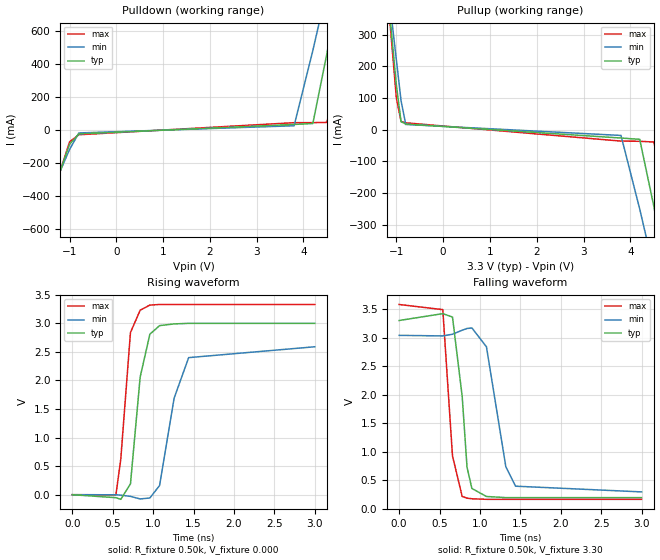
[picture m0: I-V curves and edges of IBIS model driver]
| IBIS file buffer.ibs created by s2ibis2 version 1.1
| North Carolina State University Electronics Research Laboratory  1995
[IBIS ver]   2.1
[File name]   buffer.ibs
[File Rev]   0
[Date]   April 1, 2001
[Source]   From MegaFLOPS Inc. layout and silicon models.
[Notes]   I really wouldn't try to use this driver. It's really bad.
[Disclaimer]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
[Copyright]   Copyright 2001 MegaFLOPS Inc.
|   Component MCM Driver
[Component]   MCM Driver
[Manufacturer]   MegaFLOPS Inc.
[Package]
| variable   typ   min   max
R_pkg   2.00m   1.00m   4.00m
L_pkg   0.20nH   0.10nH   0.40nH
C_pkg   2.00pF   1.00pF   4.00pF
[Pin]  signal_name   model_name   R_pin   L_pin   C_pin
out   out   driver
| in   in   dummy
gnd   gnd   GND
vdd   vdd   POWER
| Models and submodels in the file (1): driver (Output)
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|   Model driver
[Model]   driver
Model_type   Output
Polarity   Non-Inverting
C_comp   5.00pF   5.00pF   5.00pF
[Temperature Range]   27.00   100.00   0.000
[Voltage Range]   3.30V   3.00V   3.60V
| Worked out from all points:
|   slope of the pulldown table from 0 to 0.495 V, typ, clamps not added: 35.6 ohm
|   slope of the pullup table from 0 to 0.495 V, typ, clamps not added: 53 ohm
|   rising waveform, R_fixture 0.50k, V_fixture 0.000: 20-80 % time 130ps typ, 199ps min, 105ps max; typ from 0 V to 3 V
|   falling waveform, R_fixture 0.50k, V_fixture 3.30: 20-80 % time 99.1ps typ, 176ps min, 89.2ps max; typ from 3.3 V to 0.2 V
[Pulldown]
| voltage   I(typ)   I(min)   I(max)
-3.3V     -1.94A     -1.61A     -2.12A
-1.9V     -820mA     -710mA     -880mA
-1.7V     -660mA     -580mA     -700mA
-1V       -88.37mA   -120mA     -73.56mA
-800mV    -25.22mA   -19.48mA   -30.35mA
3.8V      32.13mA    24.11mA    42.78mA
4.2V      37.65mA    480mA      42.95mA
4.5V      460mA      850mA      44.43mA
4.7V      770mA      1.11A      290mA
4.9V      1.09A      1.36A      630mA
5.1V      1.4A       1.61A      980mA
6.6V      3.77A      3.52A      3.58A
[Pullup]
| voltage   I(typ)   I(min)   I(max)
-3.3V     3.79A      3.15A      4.12A
-1.5V     930mA      860mA      970mA
-1V       140mA      220mA      99.36mA
-900mV    25.45mA    91.47mA    25.83mA
-800mV    17.99mA    16.67mA    21.79mA
3.8V      -26.13mA   -17.99mA   -35.82mA
4.2V      -30.23mA   -250mA     -36.44mA
4.5V      -240mA     -440mA     -38.62mA
4.7V      -400mA     -570mA     -160mA
4.9V      -560mA     -700mA     -340mA
5.1V      -720mA     -820mA     -510mA
6.6V      -1.92A     -1.79A     -1.83A
[Ramp]
| variable   typ   min   max
dV/dt_r   1.80/0.11n   1.55/0.18n   2.00/89.01p
dV/dt_f   1.86/90.87p   1.64/0.15n   2.05/70.29p
R_load = 0.50k
[Rising Waveform]
R_fixture = 0.50k
V_fixture = 0.000
| time   V(typ)   V(min)   V(max)
0s        65.52uV    86.69uV    49.72uV
540ps     -52.23mV   -1.81mV    -1.8mV
600ps     -81.05mV   -7.86mV    620mV
720ps     190mV      -29.41mV   2.84V
840ps     2.06V      -74.24mV   3.23V
960ps     2.81V      -57.27mV   3.32V
1.08ns    2.96V      160mV      3.33V
1.26ns    2.99V      1.69V      3.33V
1.44ns    3V         2.4V       3.33V
3ns       3V         2.59V      3.33V
[Falling Waveform]
R_fixture = 0.50k
V_fixture = 3.30
| time   V(typ)   V(min)   V(max)
0s        3.3V       3.04V      3.58V
540ps     3.42V      3.03V      3.49V
660ps     3.36V      3.06V      930mV
780ps     1.97V      3.13V      220mV
840ps     730mV      3.16V      190mV
900ps     360mV      3.17V      180mV
1.08ns    220mV      2.84V      170mV
1.32ns    200mV      740mV      170mV
1.44ns    200mV      400mV      170mV
3ns       200mV      300mV      170mV
